One B-rep face of a CAD part: STEP entity #931.
In plain terms, the planar face has unit normal (1, 0, 0).
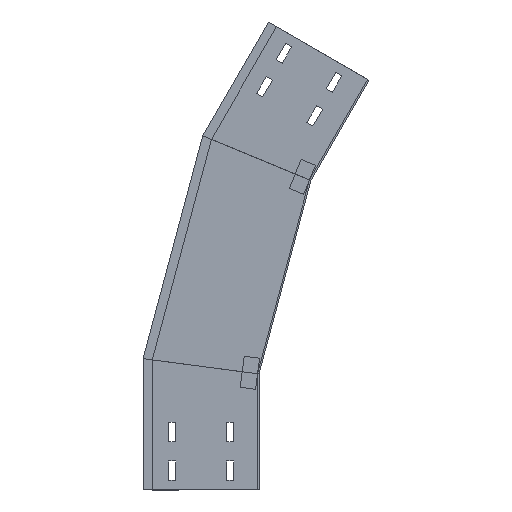
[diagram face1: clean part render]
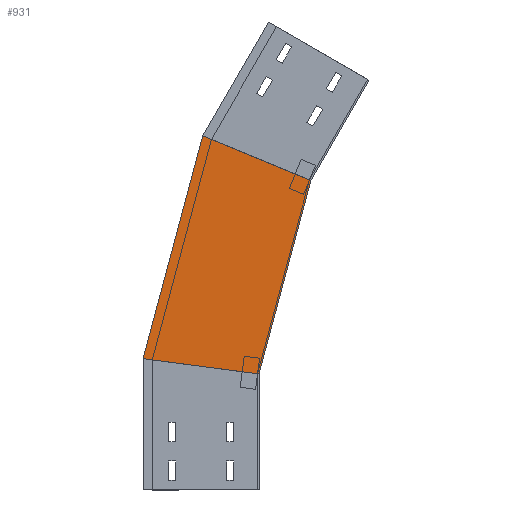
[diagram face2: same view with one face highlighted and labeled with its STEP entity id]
Its self-contained STEP definition (entity closure, numbers rounded to 3 decimals):
#50 = EDGE_CURVE ( 'NONE', #826, #1617, #1567, .T. ) ;
#68 = EDGE_CURVE ( 'NONE', #557, #135, #783, .T. ) ;
#135 = VERTEX_POINT ( 'NONE', #601 ) ;
#292 = DIRECTION ( 'NONE',  ( 0., -0.259, 0.966 ) ) ;
#306 = DIRECTION ( 'NONE',  ( 0., -0.259, 0.966 ) ) ;
#374 = VECTOR ( 'NONE', #292, 1000. ) ;
#399 = CARTESIAN_POINT ( 'NONE',  ( 0., 5.648, 128.921 ) ) ;
#519 = LINE ( 'NONE', #1167, #967 ) ;
#557 = VERTEX_POINT ( 'NONE', #784 ) ;
#562 = EDGE_CURVE ( 'NONE', #135, #1617, #2009, .T. ) ;
#601 = CARTESIAN_POINT ( 'NONE',  ( 0., 72.744, 458.073 ) ) ;
#704 = DIRECTION ( 'NONE',  ( 0., 0., -1. ) ) ;
#783 = LINE ( 'NONE', #1419, #1193 ) ;
#784 = CARTESIAN_POINT ( 'NONE',  ( 0., 150., 169.748 ) ) ;
#792 = AXIS2_PLACEMENT_3D ( 'NONE', #399, #1672, #704 ) ;
#826 = VERTEX_POINT ( 'NONE', #1023 ) ;
#868 = VECTOR ( 'NONE', #1107, 1000. ) ;
#889 = EDGE_CURVE ( 'NONE', #557, #826, #519, .T. ) ;
#896 = DIRECTION ( 'NONE',  ( 0., -0.991, -0.131 ) ) ;
#931 = ADVANCED_FACE ( 'NONE', ( #1984 ), #1819, .T. ) ;
#967 = VECTOR ( 'NONE', #896, 1000. ) ;
#989 = ORIENTED_EDGE ( 'NONE', *, *, #562, .T. ) ;
#1023 = CARTESIAN_POINT ( 'NONE',  ( 0., 0., 150. ) ) ;
#1107 = DIRECTION ( 'NONE',  ( 0., -0.924, -0.383 ) ) ;
#1167 = CARTESIAN_POINT ( 'NONE',  ( 0., -19.411, 147.444 ) ) ;
#1193 = VECTOR ( 'NONE', #306, 1000. ) ;
#1279 = ORIENTED_EDGE ( 'NONE', *, *, #68, .T. ) ;
#1320 = CARTESIAN_POINT ( 'NONE',  ( 0., -67.034, 400.175 ) ) ;
#1419 = CARTESIAN_POINT ( 'NONE',  ( 0., 150.537, 167.744 ) ) ;
#1479 = EDGE_LOOP ( 'NONE', ( #1279, #989, #1550, #1938 ) ) ;
#1550 = ORIENTED_EDGE ( 'NONE', *, *, #50, .F. ) ;
#1567 = LINE ( 'NONE', #1856, #374 ) ;
#1581 = CARTESIAN_POINT ( 'NONE',  ( 0., -100.899, 386.148 ) ) ;
#1617 = VERTEX_POINT ( 'NONE', #1320 ) ;
#1672 = DIRECTION ( 'NONE',  ( 1., 0., 0. ) ) ;
#1819 = PLANE ( 'NONE',  #792 ) ;
#1856 = CARTESIAN_POINT ( 'NONE',  ( 0., 5.648, 128.921 ) ) ;
#1938 = ORIENTED_EDGE ( 'NONE', *, *, #889, .F. ) ;
#1984 = FACE_OUTER_BOUND ( 'NONE', #1479, .T. ) ;
#2009 = LINE ( 'NONE', #1581, #868 ) ;
